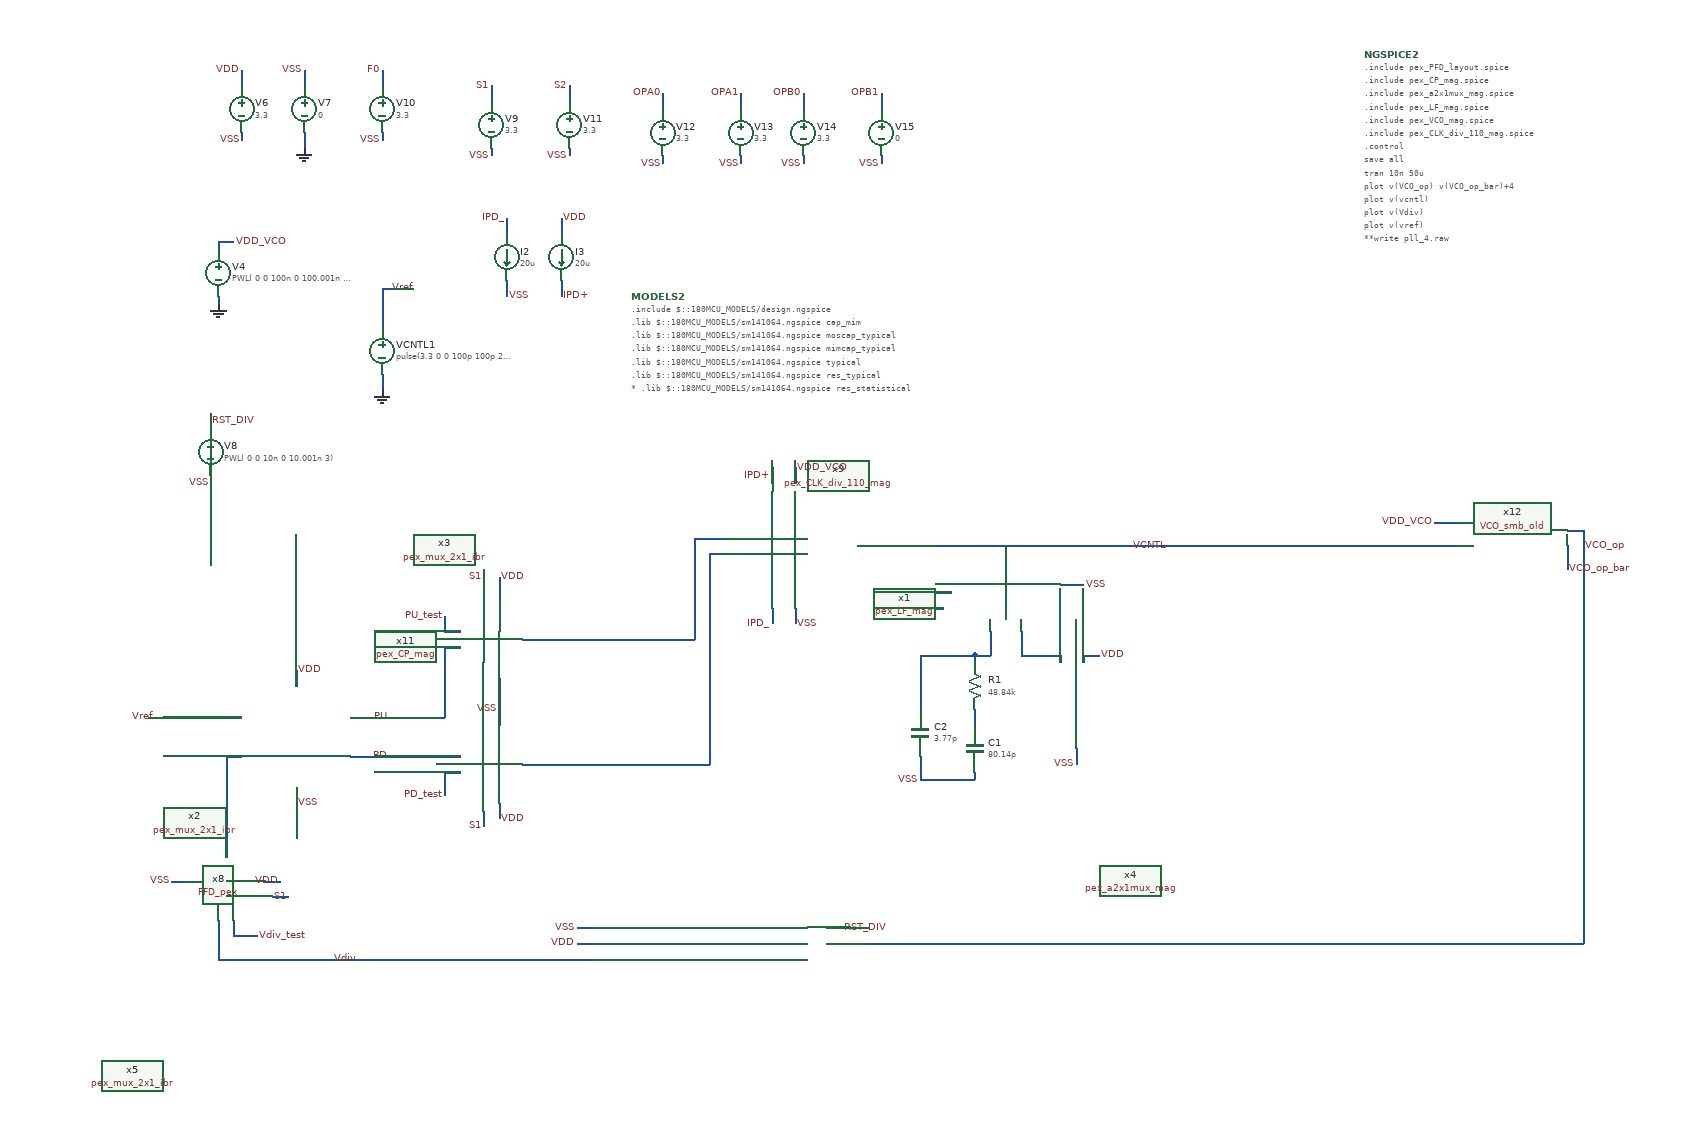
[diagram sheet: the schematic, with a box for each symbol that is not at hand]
v {xschem version=3.1.0 file_version=1.2
}
G {}
K {}
V {}
S {}
E {}
N 290 -470 290 -450 {
lab=VDD}
N 290 -320 290 -300 {
lab=VSS}
N 200 -410 220 -410 {
lab=Vref}
N 200 -360 220 -360 {
lab=#net1}
N 360 -360 380 -360 {
lab=PD}
N 120 -410 180 -410 {
lab=Vref}
N 180 -410 200 -410 {
lab=Vref}
N 380 -410 470 -410 {
lab=PU}
N 380 -360 470 -360 {
lab=PD}
N 200 -360 200 -230 {
lab=#net1}
N 210 -100 500 -100 {
lab=Vdiv}
N 200 -100 210 -100 {
lab=Vdiv}
N 360 -410 380 -410 {
lab=PU}
N 400 -850 400 -830 {
lab=GND}
N 190 -950 190 -940 {
lab=GND}
N 400 -960 420 -960 {
lab=Vref}
N 220 -1160 220 -1150 {
lab=VSS}
N 220 -1240 220 -1220 {
lab=VDD}
N 300 -1240 300 -1220 {
lab=VSS}
N 300 -1160 300 -1140 {
lab=GND}
N 500 -100 670 -100 {
lab=Vdiv}
N 1000 -120 1650 -120 {
lab=VCO_op}
N 180 -720 180 -710 {
lab=VSS}
N 180 -800 180 -780 {
lab=RST_DIV}
N 1940 -630 1940 -610 {
lab=VCO_op}
N 400 -960 400 -910 {
lab=Vref}
N 970 -120 990 -120 {
lab=VCO_op}
N 990 -120 1000 -120 {
lab=VCO_op}
N 190 -1020 190 -1010 {
lab=VDD_VCO}
N 190 -1020 210 -1020 {
lab=VDD_VCO}
N 540 -1140 540 -1130 {
lab=VSS}
N 540 -1220 540 -1200 {
lab=S1}
N 400 -1160 400 -1150 {
lab=VSS}
N 400 -1240 400 -1220 {
lab=F0}
N 640 -1140 640 -1130 {
lab=VSS}
N 640 -1220 640 -1200 {
lab=S2}
N 760 -1130 760 -1120 {
lab=VSS}
N 760 -1210 760 -1190 {
lab=OPA0}
N 860 -1130 860 -1120 {
lab=VSS}
N 860 -1210 860 -1190 {
lab=OPA1}
N 940 -1130 940 -1120 {
lab=VSS}
N 940 -1210 940 -1190 {
lab=OPB0}
N 1040 -1130 1040 -1120 {
lab=VSS}
N 1040 -1210 1040 -1190 {
lab=OPB1}
N 930 -730 930 -710 {
lab=VDD_VCO}
N 930 -550 930 -530 {
lab=VSS}
N 820 -640 840 -640 {
lab=#net2}
N 900 -730 900 -710 {
lab=IPD+}
N 900 -550 900 -530 {
lab=IPD_}
N 560 -970 560 -950 {
lab=VSS}
N 630 -970 630 -950 {
lab=IPD+}
N 560 -1050 560 -1030 {
lab=IPD_}
N 630 -1050 630 -1030 {
lab=VDD}
N 100 -410 130 -410 {
lab=Vref}
N 1940 -650 1940 -630 {
lab=VCO_op}
N 1920 -650 1940 -650 {
lab=VCO_op}
N 1920 -630 1920 -600 {
lab=VCO_op_bar}
N 660 -120 670 -120 {
lab=VDD}
N 650 -120 660 -120 {
lab=VDD}
N 650 -140 670 -140 {
lab=VSS}
N 970 -140 1000 -140 {
lab=RST_DIV}
N 1750 -660 1780 -660 {
lab=VDD_VCO}
N 1290 -370 1290 -350 {
lab=VSS}
N 1300 -490 1300 -480 {
lab=VDD}
N 1300 -490 1320 -490 {
lab=VDD}
N 1100 -550 1120 -550 {
lab=S2}
N 1100 -570 1120 -570 {
lab=VDD}
N 1270 -580 1300 -580 {
lab=VSS}
N 1090 -360 1090 -330 {
lab=VSS}
N 1090 -330 1160 -330 {
lab=VSS}
N 1090 -490 1090 -420 {
lab=#net3}
N 1090 -490 1160 -490 {
lab=#net3}
N 1160 -490 1160 -480 {
lab=#net3}
N 1120 -570 1130 -570 {
lab=VDD}
N 1080 -630 1260 -630 {
lab=VCNTL}
N 1160 -420 1160 -400 {
lab=#net4}
N 1160 -340 1160 -330 {
lab=VSS}
N 1160 -490 1180 -490 {
lab=#net3}
N 1180 -520 1180 -490 {
lab=#net3}
N 1270 -490 1270 -480 {
lab=#net5}
N 1220 -490 1270 -490 {
lab=#net5}
N 1220 -520 1220 -490 {
lab=#net5}
N 1200 -630 1200 -620 {
lab=VCNTL}
N 1260 -630 1470 -630 {
lab=VCNTL}
N 1010 -630 1080 -630 {
lab=VCNTL}
N 550 -460 550 -400 {
lab=VSS}
N 480 -500 500 -500 {
lab=PU}
N 480 -500 480 -410 {
lab=PU}
N 470 -410 480 -410 {
lab=PU}
N 530 -600 530 -570 {
lab=S1}
N 480 -520 500 -520 {
lab=PU_test}
N 480 -540 480 -520 {
lab=PU_test}
N 480 -340 500 -340 {
lab=PD_test}
N 480 -340 480 -310 {
lab=PD_test}
N 470 -360 500 -360 {
lab=PD}
N 580 -350 650 -350 {
lab=#net6}
N 830 -620 840 -620 {
lab=#net6}
N 580 -510 630 -510 {
lab=#net2}
N 810 -640 820 -640 {
lab=#net2}
N 550 -590 550 -560 {
lab=VDD}
N 550 -300 550 -280 {
lab=VDD}
N 530 -290 530 -270 {
lab=S1}
N 650 -350 820 -350 {
lab=#net6}
N 820 -620 820 -350 {
lab=#net6}
N 820 -620 830 -620 {
lab=#net6}
N 800 -640 810 -640 {
lab=#net2}
N 800 -640 800 -510 {
lab=#net2}
N 630 -510 800 -510 {
lab=#net2}
N 1470 -630 1780 -630 {
lab=VCNTL}
N 1940 -610 1940 -140 {
lab=VCO_op}
N 1650 -120 1940 -120 {
lab=VCO_op}
N 210 -150 210 -130 {
lab=PD_test}
N 210 -130 240 -130 {
lab=PD_test}
N 190 -150 190 -120 {
lab=Vdiv}
N 250 -200 270 -200 {
lab=VDD}
N 260 -180 280 -180 {
lab=S1}
N 190 -100 200 -100 {
lab=Vdiv}
N 190 -120 190 -100 {
lab=Vdiv}
N 130 -200 150 -200 {
lab=VSS}
N 1940 -140 1940 -120 {}
C {devices/lab_pin.sym} 290 -470 2 0 {name=p22 sig_type=std_logic lab=VDD}
C {devices/lab_wire.sym} 290 -300 2 0 {name=p23 sig_type=std_logic lab=VSS}
C {devices/lab_pin.sym} 370 -100 3 0 {name=p25 sig_type=std_logic lab=Vdiv
}
C {devices/lab_pin.sym} 1940 -630 2 0 {name=p26 sig_type=std_logic lab=VCO_op
}
C {devices/vsource.sym} 400 -880 0 0 {name=VCNTL1 value="pulse(3.3 0 0 100p 100p 250n 500n)"}
C {devices/gnd.sym} 400 -830 0 0 {name=l4 lab=GND}
C {devices/gnd.sym} 190 -940 0 0 {name=l5 lab=GND}
C {devices/vsource.sym} 190 -980 0 0 {name=V4 value=" PWL( 0 0 100n 0 100.001n 3.3)"}
C {devices/code_shown.sym} 1660 -1260 0 1 {name=NGSPICE2 only_toplevel=true
value="
.include "pex_PFD_layout.spice"
.include "pex_CP_mag.spice"
.include "pex_a2x1mux_mag.spice"
.include "pex_LF_mag.spice"
.include "pex_VCO_mag.spice"
.include "pex_CLK_div_110_mag.spice"
.control
save all
tran 10n 50u 
plot v(VCO_op) v(VCO_op_bar)+4
plot v(vcntl)
plot v(Vdiv)
plot v(vref)
**write pll_4.raw
.endc
"}
C {devices/vsource.sym} 220 -1190 0 0 {name=V6 value=3.3}
C {devices/vsource.sym} 300 -1190 0 0 {name=V7 value=0}
C {devices/lab_wire.sym} 300 -1240 0 0 {name=p27 sig_type=std_logic lab=VSS}
C {devices/lab_wire.sym} 220 -1150 0 0 {name=p29 sig_type=std_logic lab=VSS
}
C {devices/lab_wire.sym} 220 -1240 0 0 {name=p30 sig_type=std_logic lab=VDD}
C {devices/gnd.sym} 300 -1140 0 0 {name=l6 lab=GND}
C {devices/lab_pin.sym} 1920 -600 2 0 {name=p31 sig_type=std_logic lab=VCO_op_bar
}
C {devices/lab_pin.sym} 210 -1020 2 0 {name=p32 sig_type=std_logic lab=VDD_VCO}
C {devices/lab_pin.sym} 410 -960 2 0 {name=p33 sig_type=std_logic lab=Vref
}
C {devices/lab_wire.sym} 180 -710 0 0 {name=p34 sig_type=std_logic lab=VSS
}
C {devices/vsource.sym} 180 -750 0 0 {name=V8 value=" PWL( 0 0 10n 0 10.001n 3)"}
C {devices/lab_pin.sym} 410 -410 1 0 {name=p37 sig_type=std_logic lab=PU}
C {devices/lab_pin.sym} 410 -360 1 0 {name=p40 sig_type=std_logic lab=PD}
C {devices/vsource.sym} 540 -1170 0 0 {name=V9 value=3.3}
C {devices/lab_wire.sym} 540 -1130 0 0 {name=p41 sig_type=std_logic lab=VSS
}
C {devices/lab_wire.sym} 540 -1220 0 0 {name=p42 sig_type=std_logic lab=S1}
C {devices/vsource.sym} 400 -1190 0 0 {name=V10 value=3.3}
C {devices/lab_wire.sym} 400 -1150 0 0 {name=p43 sig_type=std_logic lab=VSS
}
C {devices/lab_wire.sym} 400 -1240 0 0 {name=p44 sig_type=std_logic lab=F0}
C {devices/vsource.sym} 640 -1170 0 0 {name=V11 value=3.3}
C {devices/lab_wire.sym} 640 -1130 0 0 {name=p45 sig_type=std_logic lab=VSS
}
C {devices/lab_wire.sym} 640 -1220 0 0 {name=p46 sig_type=std_logic lab=S2}
C {devices/vsource.sym} 760 -1160 0 0 {name=V12 value=3.3}
C {devices/lab_wire.sym} 760 -1120 0 0 {name=p59 sig_type=std_logic lab=VSS
}
C {devices/lab_wire.sym} 760 -1210 0 0 {name=p60 sig_type=std_logic lab=OPA0}
C {devices/vsource.sym} 860 -1160 0 0 {name=V13 value=3.3}
C {devices/lab_wire.sym} 860 -1120 0 0 {name=p61 sig_type=std_logic lab=VSS
}
C {devices/lab_wire.sym} 860 -1210 0 0 {name=p62 sig_type=std_logic lab=OPA1}
C {devices/vsource.sym} 940 -1160 0 0 {name=V14 value=3.3}
C {devices/lab_wire.sym} 940 -1120 0 0 {name=p63 sig_type=std_logic lab=VSS
}
C {devices/lab_wire.sym} 940 -1210 0 0 {name=p64 sig_type=std_logic lab=OPB0
}
C {devices/vsource.sym} 1040 -1160 0 0 {name=V15 value=0}
C {devices/lab_wire.sym} 1040 -1120 0 0 {name=p65 sig_type=std_logic lab=VSS
}
C {devices/lab_wire.sym} 1040 -1210 0 0 {name=p66 sig_type=std_logic lab=OPB1}
C {devices/lab_pin.sym} 180 -790 2 0 {name=p67 sig_type=std_logic lab=RST_DIV}
C {devices/lab_wire.sym} 930 -530 2 0 {name=p68 sig_type=std_logic lab=VSS}
C {devices/lab_wire.sym} 900 -720 0 0 {name=p70 sig_type=std_logic lab=IPD+}
C {devices/lab_wire.sym} 900 -530 0 0 {name=p71 sig_type=std_logic lab=IPD_}
C {devices/isource.sym} 560 -1000 0 0 {name=I2 value=20u}
C {devices/isource.sym} 630 -1000 0 0 {name=I3 value=20u}
C {devices/lab_wire.sym} 560 -1050 0 0 {name=p72 sig_type=std_logic lab=IPD_}
C {devices/lab_wire.sym} 630 -950 2 0 {name=p73 sig_type=std_logic lab=IPD+}
C {devices/lab_wire.sym} 560 -950 2 0 {name=p74 sig_type=std_logic lab=VSS}
C {devices/lab_wire.sym} 630 -1050 2 0 {name=p75 sig_type=std_logic lab=VDD}
C {devices/lab_pin.sym} 110 -410 0 0 {name=p76 sig_type=std_logic lab=Vref
}
C {devices/code_shown.sym} 720 -950 0 0 {name=MODELS2 only_toplevel=true
format="tcleval( @value )"
value="
.include $::180MCU_MODELS/design.ngspice
.lib $::180MCU_MODELS/sm141064.ngspice cap_mim
.lib $::180MCU_MODELS/sm141064.ngspice moscap_typical
.lib $::180MCU_MODELS/sm141064.ngspice mimcap_typical
.lib $::180MCU_MODELS/sm141064.ngspice typical
.lib $::180MCU_MODELS/sm141064.ngspice res_typical
* .lib $::180MCU_MODELS/sm141064.ngspice res_statistical
"}
C {PFD_pex.sym} 0 -200 0 0 {name=x8}
C {devices/lab_wire.sym} 650 -140 0 0 {name=p78 sig_type=std_logic lab=VSS}
C {devices/lab_pin.sym} 650 -120 0 0 {name=p79 sig_type=std_logic lab=VDD}
C {devices/lab_pin.sym} 990 -140 2 0 {name=p80 sig_type=std_logic lab=RST_DIV}
C {pex_CLK_div_110_mag.sym} 820 -120 0 1 {name=x9}
C {pex_CP_mag.sym} 350 -430 0 0 {name=x11}
C {devices/lab_pin.sym} 930 -730 2 0 {name=p81 sig_type=std_logic lab=VDD_VCO}
C {VCO_smb_old.sym} 1930 -640 0 0 {name=x12}
C {devices/lab_pin.sym} 1750 -660 0 0 {name=p89 sig_type=std_logic lab=VDD_VCO}
C {devices/lab_wire.sym} 1290 -350 2 1 {name=p5 sig_type=std_logic lab=VSS}
C {devices/lab_wire.sym} 1360 -630 2 0 {name=p20 sig_type=std_logic lab=VCNTL}
C {devices/lab_wire.sym} 1320 -490 0 1 {name=p21 sig_type=std_logic lab=VDD}
C {devices/lab_wire.sym} 1300 -580 2 0 {name=p6 sig_type=std_logic lab=VSS}
C {devices/lab_wire.sym} 1100 -570 2 1 {name=p1 sig_type=std_logic lab=VDD}
C {devices/lab_wire.sym} 1100 -550 1 1 {name=p2 sig_type=std_logic lab=S2}
C {devices/capa.sym} 1160 -370 0 0 {name=C1
m=1
value=80.14p
footprint=1206
device="ceramic capacitor"}
C {devices/capa.sym} 1090 -390 0 0 {name=C2
m=1
value=3.77p
footprint=1206
device="ceramic capacitor"}
C {devices/res.sym} 1160 -450 0 0 {name=R1
value=48.84k
footprint=1206
device=resistor
m=1}
C {devices/lab_wire.sym} 1090 -330 2 1 {name=p3 sig_type=std_logic lab=VSS}
C {pex_a2x1mux_mag.sym} 1360 -200 3 0 {name=x4}
C {pex_LF_mag.sym} 1430 -320 0 1 {name=x1}
C {pex_mux_2x1_ibr.sym} 300 -390 0 0 {name=x2}
C {pex_mux_2x1_ibr.sym} 300 -470 2 1 {name=x3}
C {devices/lab_wire.sym} 550 -420 0 0 {name=p4 sig_type=std_logic lab=VSS
}
C {devices/lab_wire.sym} 550 -590 2 0 {name=p7 sig_type=std_logic lab=VDD}
C {devices/lab_wire.sym} 550 -280 2 0 {name=p8 sig_type=std_logic lab=VDD}
C {devices/lab_wire.sym} 530 -590 0 0 {name=p10 sig_type=std_logic lab=S1}
C {devices/lab_wire.sym} 530 -270 0 0 {name=p9 sig_type=std_logic lab=S1}
C {devices/lab_pin.sym} 480 -540 0 0 {name=p11 sig_type=std_logic lab=PU_test}
C {devices/lab_pin.sym} 480 -310 0 0 {name=p12 sig_type=std_logic lab=PD_test}
C {pex_mux_2x1_ibr.sym} 80 50 1 1 {name=x5}
C {devices/lab_wire.sym} 130 -200 3 0 {name=p13 sig_type=std_logic lab=VSS
}
C {devices/lab_wire.sym} 270 -200 1 0 {name=p14 sig_type=std_logic lab=VDD}
C {devices/lab_wire.sym} 280 -180 3 0 {name=p15 sig_type=std_logic lab=S1}
C {devices/lab_pin.sym} 240 -130 2 0 {name=p16 sig_type=std_logic lab=Vdiv_test}
